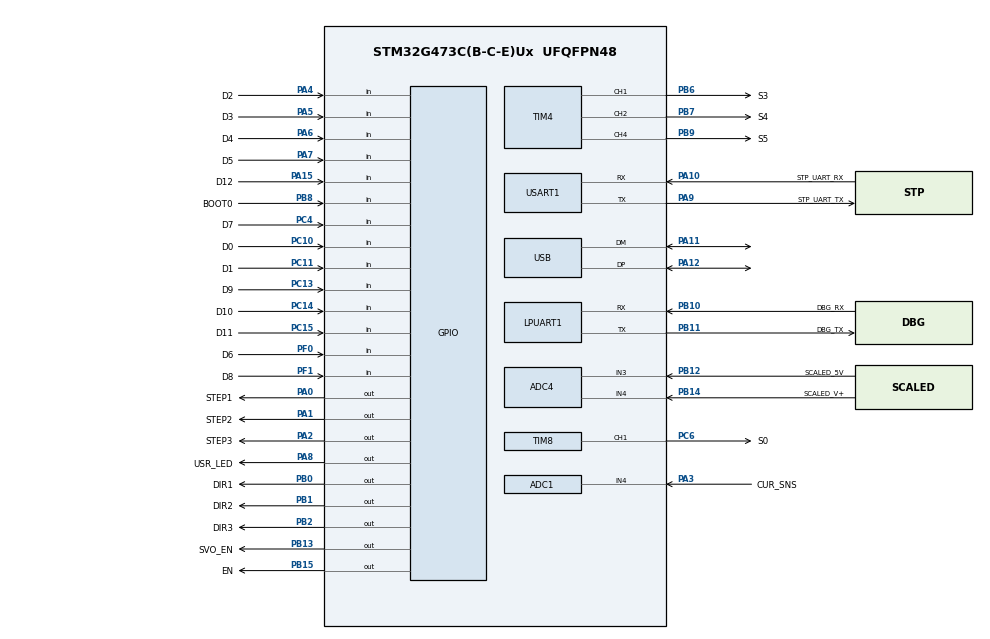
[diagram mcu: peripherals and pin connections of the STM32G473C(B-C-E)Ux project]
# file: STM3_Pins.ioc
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ADC1.Channel-0\#ChannelRegularConversion=ADC_CHANNEL_4
ADC1.NbrOfConversionFlag=1
ADC1.OffsetNumber-0\#ChannelRegularConversion=ADC_OFFSET_NONE
ADC1.Rank-0\#ChannelRegularConversion=1
ADC1.SamplingTime-0\#ChannelRegularConversion=ADC_SAMPLETIME_2CYCLES_5
ADC1.master=1
ADC4.Channel-0\#ChannelRegularConversion=ADC_CHANNEL_3
ADC4.NbrOfConversionFlag=1
ADC4.OffsetNumber-0\#ChannelRegularConversion=ADC_OFFSET_NONE
ADC4.Rank-0\#ChannelRegularConversion=1
ADC4.SamplingTime-0\#ChannelRegularConversion=ADC_SAMPLETIME_2CYCLES_5
Mcu.Family=STM32G4
Mcu.Name=STM32G473C(B-C-E)Ux
Mcu.Package=UFQFPN48
NVIC.PriorityGroup=NVIC_PRIORITYGROUP_4
NVIC.TIM6_DAC_IRQn=true\:0\:0\:false\:false\:true\:true\:true
NVIC.USB_LP_IRQn=true\:0\:0\:false\:false\:true\:false\:true
PA0.GPIO_Label=STEP1
PA0.Signal=GPIO_Output
PA1.GPIO_Label=STEP2
PA1.Signal=GPIO_Output
PA10.GPIO_Label=STP_UART_RX
PA10.Mode=Asynchronous
PA10.Signal=USART1_RX
PA11.Mode=Device
PA11.Signal=USB_DM
PA12.Mode=Device
PA12.Signal=USB_DP
PA13.GPIO_Label=SWDIO
PA13.Mode=Serial_Wire
PA13.Signal=SYS_JTMS-SWDIO
PA14.GPIO_Label=SWCLK
PA14.Mode=Serial_Wire
PA14.Signal=SYS_JTCK-SWCLK
PA15.GPIO_Label=D12
PA15.Signal=GPIO_Input
PA2.GPIO_Label=STEP3
PA2.Signal=GPIO_Output
PA3.GPIO_Label=CUR_SNS
PA3.Mode=IN4-Single-Ended
PA3.Signal=ADC1_IN4
PA4.GPIO_Label=D2
PA4.Signal=GPIO_Input
PA5.GPIO_Label=D3
PA5.Signal=GPIO_Input
PA6.GPIO_Label=D4
PA6.Signal=GPIO_Input
PA7.GPIO_Label=D5
PA7.Signal=GPIO_Input
PA8.GPIO_Label=USR_LED
PA8.Signal=GPIO_Output
PA9.GPIO_Label=STP_UART_TX
PA9.Mode=Asynchronous
PA9.Signal=USART1_TX
PB0.GPIO_Label=DIR1
PB0.Signal=GPIO_Output
PB1.GPIO_Label=DIR2
PB1.Signal=GPIO_Output
PB10.GPIO_Label=DBG_RX
PB10.Mode=Asynchronous
PB10.Signal=LPUART1_RX
PB11.GPIO_Label=DBG_TX
PB11.Mode=Asynchronous
PB11.Signal=LPUART1_TX
PB12.GPIO_Label=SCALED_5V
PB12.Mode=IN3-Single-Ended
PB12.Signal=ADC4_IN3
PB13.GPIO_Label=SVO_EN
PB13.Signal=GPIO_Output
PB14.GPIO_Label=SCALED_V+
PB14.Mode=IN4-Single-Ended
PB14.Signal=ADC4_IN4
PB15.GPIO_Label=EN
PB15.Signal=GPIO_Output
PB2.GPIO_Label=DIR3
PB2.Signal=GPIO_Output
PB3.GPIO_Label=SWO
PB3.Signal=SYS_JTDO-SWO
PB4.GPIO_Label=S1
PB4.Signal=S_TIM3_CH1
PB5.GPIO_Label=S2
PB5.Signal=S_TIM3_CH2
PB6.GPIO_Label=S3
PB6.Signal=S_TIM4_CH1
PB7.GPIO_Label=S4
PB7.Signal=S_TIM4_CH2
PB8-BOOT0.GPIO_Label=BOOT0
PB8-BOOT0.Signal=GPIO_Input
PB9.GPIO_Label=S5
PB9.Signal=S_TIM4_CH4
PC10.GPIO_Label=D0
PC10.Signal=GPIO_Input
PC11.GPIO_Label=D1
PC11.Signal=GPIO_Input
PC13.GPIO_Label=D9
PC13.Signal=GPIO_Input
PC14-OSC32_IN.GPIO_Label=D10
PC14-OSC32_IN.Signal=GPIO_Input
PC15-OSC32_OUT.GPIO_Label=D11
PC15-OSC32_OUT.Signal=GPIO_Input
PC4.GPIO_Label=D7
PC4.Signal=GPIO_Input
PC6.GPIO_Label=S0
PC6.Signal=S_TIM8_CH1
PF0-OSC_IN.GPIO_Label=D6
PF0-OSC_IN.Signal=GPIO_Input
PF1-OSC_OUT.GPIO_Label=D8
PF1-OSC_OUT.Signal=GPIO_Input
ProjectManager.HeapSize=0x200
ProjectManager.StackSize=0x400
ProjectManager.TargetToolchain=STM32CubeIDE
RCC.ADC12Freq_Value=150000000
RCC.ADC345Freq_Value=150000000
RCC.AHBFreq_Value=150000000
RCC.APB1Freq_Value=150000000
RCC.APB1TimFreq_Value=150000000
RCC.APB2Freq_Value=150000000
RCC.APB2TimFreq_Value=150000000
RCC.CK48CLockSelection=RCC_USBCLKSOURCE_HSI48
RCC.CortexFreq_Value=150000000
RCC.EXTERNAL_CLOCK_VALUE=12288000
RCC.HCLKFreq_Value=150000000
RCC.HSE_VALUE=8000000
RCC.HSI48_VALUE=48000000
RCC.HSI_VALUE=16000000
RCC.LSE_VALUE=32768
RCC.PLLM=RCC_PLLM_DIV4
RCC.PLLN=75
RCC.PLLQ=RCC_PLLQ_DIV6
RCC.SYSCLKFreq_VALUE=150000000
RCC.SYSCLKSource=RCC_SYSCLKSOURCE_PLLCLK
RCC.USBFreq_Value=48000000
RCC.VCOOutputFreq_Value=300000000
SH.S_TIM3_CH1.0=TIM3_CH1
SH.S_TIM3_CH2.0=TIM3_CH2
SH.S_TIM4_CH1.0=TIM4_CH1,Output Compare1 CH1
SH.S_TIM4_CH2.0=TIM4_CH2,Output Compare2 CH2
SH.S_TIM4_CH4.0=TIM4_CH4,Output Compare4 CH4
SH.S_TIM8_CH1.0=TIM8_CH1,PWM Generation1 CH1
TIM4.Channel-Output\ Compare1\ CH1=TIM_CHANNEL_1
TIM4.Channel-Output\ Compare2\ CH2=TIM_CHANNEL_2
TIM4.Channel-Output\ Compare4\ CH4=TIM_CHANNEL_4
TIM6.PeriodNoDither=1700
TIM8.Channel-PWM\ Generation1\ CH1=TIM_CHANNEL_1
USART1.VirtualMode-Asynchronous=VM_ASYNC
USB_DEVICE.CLASS_NAME_FS=CDC
USB_DEVICE.VirtualMode=Cdc
USB_DEVICE.VirtualModeFS=Cdc_FS
VP_RCC_VS_USB.Mode=USB_FS
VP_SYS_VS_DBSignals.Mode=DisableDeadBatterySignals
VP_TIM2_VS_ClockSourceINT.Mode=Internal
VP_TIM3_VS_ClockSourceINT.Mode=Internal
VP_TIM4_VS_ClockSourceINT.Mode=Internal
VP_TIM6_VS_ClockSourceINT.Mode=Enable_Timer
VP_TIM8_VS_ClockSourceINT.Mode=Internal
VP_USB_DEVICE_VS_USB_DEVICE_CDC_FS.Mode=CDC_FS
board=custom

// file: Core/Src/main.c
/* USER CODE BEGIN Header */
/**
  ******************************************************************************
  * @file           : main.c
  * @brief          : Main program body
  ******************************************************************************
  * @attention
  *
  * <h2><center>&copy; Copyright (c) 2020 STMicroelectronics.
  * All rights reserved.</center></h2>
  *
  * This software component is licensed by ST under BSD 3-Clause license,
  * the "License"; You may not use this file except in compliance with the
  * License. You may obtain a copy of the License at:
  *                        opensource.org/licenses/BSD-3-Clause
  *
  ******************************************************************************
  */
/* USER CODE END Header */
#include "main.h"
#include "usb_device.h"

/* USER CODE BEGIN Includes */
#include "usbd_cdc_if.h"
#include "retarget.h"
#include "isr.h"
#include "debug.h"

/* USER CODE END Includes */

ADC_HandleTypeDef hadc1;
ADC_HandleTypeDef hadc4;

UART_HandleTypeDef hlpuart1;
UART_HandleTypeDef huart1;

TIM_HandleTypeDef htim2;
TIM_HandleTypeDef htim3;
TIM_HandleTypeDef htim4;
TIM_HandleTypeDef htim6;
TIM_HandleTypeDef htim8;

void SystemClock_Config(void);
static void MX_GPIO_Init(void);
static void MX_TIM2_Init(void);
static void MX_TIM3_Init(void);
static void MX_TIM4_Init(void);
static void MX_USART1_UART_Init(void);
static void MX_ADC4_Init(void);
static void MX_LPUART1_UART_Init(void);
static void MX_ADC1_Init(void);
static void MX_TIM8_Init(void);
static void MX_TIM6_Init(void);

/* USER CODE BEGIN 0 */

void HAL_TIM_PeriodElapsedCallback(TIM_HandleTypeDef *htim)
{
  if (htim == &htim6)
  {
    high_ISR();
  }
}

/* USER CODE END 0 */

int main(void)
{

  /* MCU Configuration--------------------------------------------------------*/

  /* Reset of all peripherals, Initializes the Flash interface and the Systick. */
  HAL_Init();

  /* Configure the system clock */
  SystemClock_Config();

  /* Initialize all configured peripherals */
  MX_GPIO_Init();
  MX_USB_Device_Init();
  MX_TIM2_Init();
  MX_TIM3_Init();
  MX_TIM4_Init();
  MX_USART1_UART_Init();
  MX_ADC4_Init();
  MX_LPUART1_UART_Init();
  MX_ADC1_Init();
  MX_TIM8_Init();
  MX_TIM6_Init();
  /* USER CODE BEGIN 2 */
  RetargetInit();
  DebugInit();
  /* USER CODE END 2 */

  /* Infinite loop */
  /* USER CODE BEGIN WHILE */
  while (1)
  {
    DEBUG_G0_SET();
    DEBUG_G0_RESET();
    /* USER CODE END WHILE */

  }
}

void SystemClock_Config(void)
{
  RCC_OscInitTypeDef RCC_OscInitStruct = {0};
  RCC_ClkInitTypeDef RCC_ClkInitStruct = {0};
  RCC_PeriphCLKInitTypeDef PeriphClkInit = {0};
  RCC_CRSInitTypeDef pInit = {0};

  /** Configure the main internal regulator output voltage
  */
  HAL_PWREx_ControlVoltageScaling(PWR_REGULATOR_VOLTAGE_SCALE1_BOOST);
  /** Initializes the RCC Oscillators according to the specified parameters
  * in the RCC_OscInitTypeDef structure.
  */
  RCC_OscInitStruct.OscillatorType = RCC_OSCILLATORTYPE_HSI|RCC_OSCILLATORTYPE_HSI48;
  RCC_OscInitStruct.HSIState = RCC_HSI_ON;
  RCC_OscInitStruct.HSICalibrationValue = RCC_HSICALIBRATION_DEFAULT;
  RCC_OscInitStruct.HSI48State = RCC_HSI48_ON;
  RCC_OscInitStruct.PLL.PLLState = RCC_PLL_ON;
  RCC_OscInitStruct.PLL.PLLSource = RCC_PLLSOURCE_HSI;
  RCC_OscInitStruct.PLL.PLLM = RCC_PLLM_DIV4;
  RCC_OscInitStruct.PLL.PLLN = 85;
  RCC_OscInitStruct.PLL.PLLP = RCC_PLLP_DIV2;
  RCC_OscInitStruct.PLL.PLLQ = RCC_PLLQ_DIV6;
  RCC_OscInitStruct.PLL.PLLR = RCC_PLLR_DIV2;
  if (HAL_RCC_OscConfig(&RCC_OscInitStruct) != HAL_OK)
  {
    Error_Handler();
  }
  /** Initializes the CPU, AHB and APB buses clocks
  */
  RCC_ClkInitStruct.ClockType = RCC_CLOCKTYPE_HCLK|RCC_CLOCKTYPE_SYSCLK
                              |RCC_CLOCKTYPE_PCLK1|RCC_CLOCKTYPE_PCLK2;
  RCC_ClkInitStruct.SYSCLKSource = RCC_SYSCLKSOURCE_PLLCLK;
  RCC_ClkInitStruct.AHBCLKDivider = RCC_SYSCLK_DIV1;
  RCC_ClkInitStruct.APB1CLKDivider = RCC_HCLK_DIV1;
  RCC_ClkInitStruct.APB2CLKDivider = RCC_HCLK_DIV1;

  if (HAL_RCC_ClockConfig(&RCC_ClkInitStruct, FLASH_LATENCY_4) != HAL_OK)
  {
    Error_Handler();
  }
  /** Initializes the peripherals clocks
  */
  PeriphClkInit.PeriphClockSelection = RCC_PERIPHCLK_USART1|RCC_PERIPHCLK_LPUART1
                              |RCC_PERIPHCLK_USB|RCC_PERIPHCLK_ADC12
                              |RCC_PERIPHCLK_ADC345;
  PeriphClkInit.Usart1ClockSelection = RCC_USART1CLKSOURCE_PCLK2;
  PeriphClkInit.Lpuart1ClockSelection = RCC_LPUART1CLKSOURCE_PCLK1;
  PeriphClkInit.UsbClockSelection = RCC_USBCLKSOURCE_HSI48;
  PeriphClkInit.Adc12ClockSelection = RCC_ADC12CLKSOURCE_SYSCLK;
  PeriphClkInit.Adc345ClockSelection = RCC_ADC345CLKSOURCE_SYSCLK;
  if (HAL_RCCEx_PeriphCLKConfig(&PeriphClkInit) != HAL_OK)
  {
    Error_Handler();
  }
  /** Configures CRS
  */
  pInit.Prescaler = RCC_CRS_SYNC_DIV1;
  pInit.Source = RCC_CRS_SYNC_SOURCE_USB;
  pInit.Polarity = RCC_CRS_SYNC_POLARITY_RISING;
  pInit.ReloadValue = __HAL_RCC_CRS_RELOADVALUE_CALCULATE(48000000,1000);
  pInit.ErrorLimitValue = 34;
  pInit.HSI48CalibrationValue = 32;

  HAL_RCCEx_CRSConfig(&pInit);
}

static void MX_ADC1_Init(void)
{

  ADC_MultiModeTypeDef multimode = {0};
  ADC_ChannelConfTypeDef sConfig = {0};

  /** Common config
  */
  hadc1.Instance = ADC1;
  hadc1.Init.ClockPrescaler = ADC_CLOCK_SYNC_PCLK_DIV4;
  hadc1.Init.Resolution = ADC_RESOLUTION_12B;
  hadc1.Init.DataAlign = ADC_DATAALIGN_RIGHT;
  hadc1.Init.GainCompensation = 0;
  hadc1.Init.ScanConvMode = ADC_SCAN_DISABLE;
  hadc1.Init.EOCSelection = ADC_EOC_SINGLE_CONV;
  hadc1.Init.LowPowerAutoWait = DISABLE;
  hadc1.Init.ContinuousConvMode = DISABLE;
  hadc1.Init.NbrOfConversion = 1;
  hadc1.Init.DiscontinuousConvMode = DISABLE;
  hadc1.Init.ExternalTrigConv = ADC_SOFTWARE_START;
  hadc1.Init.ExternalTrigConvEdge = ADC_EXTERNALTRIGCONVEDGE_NONE;
  hadc1.Init.DMAContinuousRequests = DISABLE;
  hadc1.Init.Overrun = ADC_OVR_DATA_PRESERVED;
  hadc1.Init.OversamplingMode = DISABLE;
  if (HAL_ADC_Init(&hadc1) != HAL_OK)
  {
    Error_Handler();
  }
  /** Configure the ADC multi-mode
  */
  multimode.Mode = ADC_MODE_INDEPENDENT;
  if (HAL_ADCEx_MultiModeConfigChannel(&hadc1, &multimode) != HAL_OK)
  {
    Error_Handler();
  }
  /** Configure Regular Channel
  */
  sConfig.Channel = ADC_CHANNEL_4;
  sConfig.Rank = ADC_REGULAR_RANK_1;
  sConfig.SamplingTime = ADC_SAMPLETIME_2CYCLES_5;
  sConfig.SingleDiff = ADC_SINGLE_ENDED;
  sConfig.OffsetNumber = ADC_OFFSET_NONE;
  sConfig.Offset = 0;
  if (HAL_ADC_ConfigChannel(&hadc1, &sConfig) != HAL_OK)
  {
    Error_Handler();
  }

}

static void MX_ADC4_Init(void)
{

  ADC_ChannelConfTypeDef sConfig = {0};

  /** Common config
  */
  hadc4.Instance = ADC4;
  hadc4.Init.ClockPrescaler = ADC_CLOCK_SYNC_PCLK_DIV4;
  hadc4.Init.Resolution = ADC_RESOLUTION_12B;
  hadc4.Init.DataAlign = ADC_DATAALIGN_RIGHT;
  hadc4.Init.GainCompensation = 0;
  hadc4.Init.ScanConvMode = ADC_SCAN_DISABLE;
  hadc4.Init.EOCSelection = ADC_EOC_SINGLE_CONV;
  hadc4.Init.LowPowerAutoWait = DISABLE;
  hadc4.Init.ContinuousConvMode = DISABLE;
  hadc4.Init.NbrOfConversion = 1;
  hadc4.Init.DiscontinuousConvMode = DISABLE;
  hadc4.Init.ExternalTrigConv = ADC_SOFTWARE_START;
  hadc4.Init.ExternalTrigConvEdge = ADC_EXTERNALTRIGCONVEDGE_NONE;
  hadc4.Init.DMAContinuousRequests = DISABLE;
  hadc4.Init.Overrun = ADC_OVR_DATA_PRESERVED;
  hadc4.Init.OversamplingMode = DISABLE;
  if (HAL_ADC_Init(&hadc4) != HAL_OK)
  {
    Error_Handler();
  }
  /** Configure Regular Channel
  */
  sConfig.Channel = ADC_CHANNEL_3;
  sConfig.Rank = ADC_REGULAR_RANK_1;
  sConfig.SamplingTime = ADC_SAMPLETIME_2CYCLES_5;
  sConfig.SingleDiff = ADC_SINGLE_ENDED;
  sConfig.OffsetNumber = ADC_OFFSET_NONE;
  sConfig.Offset = 0;
  if (HAL_ADC_ConfigChannel(&hadc4, &sConfig) != HAL_OK)
  {
    Error_Handler();
  }

}

static void MX_LPUART1_UART_Init(void)
{

  hlpuart1.Instance = LPUART1;
  hlpuart1.Init.BaudRate = 209700;
  hlpuart1.Init.WordLength = UART_WORDLENGTH_8B;
  hlpuart1.Init.StopBits = UART_STOPBITS_1;
  hlpuart1.Init.Parity = UART_PARITY_NONE;
  hlpuart1.Init.Mode = UART_MODE_TX_RX;
  hlpuart1.Init.HwFlowCtl = UART_HWCONTROL_NONE;
  hlpuart1.Init.OneBitSampling = UART_ONE_BIT_SAMPLE_DISABLE;
  hlpuart1.AdvancedInit.AdvFeatureInit = UART_ADVFEATURE_NO_INIT;
  if (HAL_UART_Init(&hlpuart1) != HAL_OK)
  {
    Error_Handler();
  }
  if (HAL_UARTEx_SetTxFifoThreshold(&hlpuart1, UART_TXFIFO_THRESHOLD_1_8) != HAL_OK)
  {
    Error_Handler();
  }
  if (HAL_UARTEx_SetRxFifoThreshold(&hlpuart1, UART_RXFIFO_THRESHOLD_1_8) != HAL_OK)
  {
    Error_Handler();
  }
  if (HAL_UARTEx_DisableFifoMode(&hlpuart1) != HAL_OK)
  {
    Error_Handler();
  }

}

static void MX_USART1_UART_Init(void)
{

  huart1.Instance = USART1;
  huart1.Init.BaudRate = 115200;
  huart1.Init.WordLength = UART_WORDLENGTH_8B;
  huart1.Init.StopBits = UART_STOPBITS_1;
  huart1.Init.Parity = UART_PARITY_NONE;
  huart1.Init.Mode = UART_MODE_TX_RX;
  huart1.Init.HwFlowCtl = UART_HWCONTROL_NONE;
  huart1.Init.OverSampling = UART_OVERSAMPLING_16;
  huart1.Init.OneBitSampling = UART_ONE_BIT_SAMPLE_DISABLE;
  huart1.Init.ClockPrescaler = UART_PRESCALER_DIV1;
  huart1.AdvancedInit.AdvFeatureInit = UART_ADVFEATURE_NO_INIT;
  if (HAL_UART_Init(&huart1) != HAL_OK)
  {
    Error_Handler();
  }
  if (HAL_UARTEx_SetTxFifoThreshold(&huart1, UART_TXFIFO_THRESHOLD_1_8) != HAL_OK)
  {
    Error_Handler();
  }
  if (HAL_UARTEx_SetRxFifoThreshold(&huart1, UART_RXFIFO_THRESHOLD_1_8) != HAL_OK)
  {
    Error_Handler();
  }
  if (HAL_UARTEx_DisableFifoMode(&huart1) != HAL_OK)
  {
    Error_Handler();
  }

}

static void MX_TIM2_Init(void)
{

  TIM_ClockConfigTypeDef sClockSourceConfig = {0};
  TIM_MasterConfigTypeDef sMasterConfig = {0};

  htim2.Instance = TIM2;
  htim2.Init.Prescaler = 0;
  htim2.Init.CounterMode = TIM_COUNTERMODE_UP;
  htim2.Init.Period = 4.294967295E9;
  htim2.Init.ClockDivision = TIM_CLOCKDIVISION_DIV1;
  htim2.Init.AutoReloadPreload = TIM_AUTORELOAD_PRELOAD_DISABLE;
  if (HAL_TIM_Base_Init(&htim2) != HAL_OK)
  {
    Error_Handler();
  }
  sClockSourceConfig.ClockSource = TIM_CLOCKSOURCE_INTERNAL;
  if (HAL_TIM_ConfigClockSource(&htim2, &sClockSourceConfig) != HAL_OK)
  {
    Error_Handler();
  }
  sMasterConfig.MasterOutputTrigger = TIM_TRGO_RESET;
  sMasterConfig.MasterSlaveMode = TIM_MASTERSLAVEMODE_DISABLE;
  if (HAL_TIMEx_MasterConfigSynchronization(&htim2, &sMasterConfig) != HAL_OK)
  {
    Error_Handler();
  }

}

static void MX_TIM3_Init(void)
{

  TIM_ClockConfigTypeDef sClockSourceConfig = {0};
  TIM_MasterConfigTypeDef sMasterConfig = {0};

  htim3.Instance = TIM3;
  htim3.Init.Prescaler = 0;
  htim3.Init.CounterMode = TIM_COUNTERMODE_UP;
  htim3.Init.Period = 65535;
  htim3.Init.ClockDivision = TIM_CLOCKDIVISION_DIV1;
  htim3.Init.AutoReloadPreload = TIM_AUTORELOAD_PRELOAD_DISABLE;
  if (HAL_TIM_Base_Init(&htim3) != HAL_OK)
  {
    Error_Handler();
  }
  sClockSourceConfig.ClockSource = TIM_CLOCKSOURCE_INTERNAL;
  if (HAL_TIM_ConfigClockSource(&htim3, &sClockSourceConfig) != HAL_OK)
  {
    Error_Handler();
  }
  sMasterConfig.MasterOutputTrigger = TIM_TRGO_RESET;
  sMasterConfig.MasterSlaveMode = TIM_MASTERSLAVEMODE_DISABLE;
  if (HAL_TIMEx_MasterConfigSynchronization(&htim3, &sMasterConfig) != HAL_OK)
  {
    Error_Handler();
  }

}

static void MX_TIM4_Init(void)
{

  TIM_ClockConfigTypeDef sClockSourceConfig = {0};
  TIM_MasterConfigTypeDef sMasterConfig = {0};
  TIM_OC_InitTypeDef sConfigOC = {0};

  htim4.Instance = TIM4;
  htim4.Init.Prescaler = 0;
  htim4.Init.CounterMode = TIM_COUNTERMODE_UP;
  htim4.Init.Period = 65535;
  htim4.Init.ClockDivision = TIM_CLOCKDIVISION_DIV1;
  htim4.Init.AutoReloadPreload = TIM_AUTORELOAD_PRELOAD_DISABLE;
  if (HAL_TIM_Base_Init(&htim4) != HAL_OK)
  {
    Error_Handler();
  }
  sClockSourceConfig.ClockSource = TIM_CLOCKSOURCE_INTERNAL;
  if (HAL_TIM_ConfigClockSource(&htim4, &sClockSourceConfig) != HAL_OK)
  {
    Error_Handler();
  }
  if (HAL_TIM_OC_Init(&htim4) != HAL_OK)
  {
    Error_Handler();
  }
  sMasterConfig.MasterOutputTrigger = TIM_TRGO_RESET;
  sMasterConfig.MasterSlaveMode = TIM_MASTERSLAVEMODE_DISABLE;
  if (HAL_TIMEx_MasterConfigSynchronization(&htim4, &sMasterConfig) != HAL_OK)
  {
    Error_Handler();
  }
  sConfigOC.OCMode = TIM_OCMODE_TIMING;
  sConfigOC.Pulse = 0;
  sConfigOC.OCPolarity = TIM_OCPOLARITY_HIGH;
  sConfigOC.OCFastMode = TIM_OCFAST_DISABLE;
  if (HAL_TIM_OC_ConfigChannel(&htim4, &sConfigOC, TIM_CHANNEL_1) != HAL_OK)
  {
    Error_Handler();
  }
  sConfigOC.Pulse = 0;
  if (HAL_TIM_OC_ConfigChannel(&htim4, &sConfigOC, TIM_CHANNEL_2) != HAL_OK)
  {
    Error_Handler();
  }
  sConfigOC.Pulse = 0;
  if (HAL_TIM_OC_ConfigChannel(&htim4, &sConfigOC, TIM_CHANNEL_4) != HAL_OK)
  {
    Error_Handler();
  }
  HAL_TIM_MspPostInit(&htim4);

}

static void MX_TIM6_Init(void)
{

  TIM_MasterConfigTypeDef sMasterConfig = {0};

  htim6.Instance = TIM6;
  htim6.Init.Prescaler = 0;
  htim6.Init.CounterMode = TIM_COUNTERMODE_UP;
  htim6.Init.Period = 1700;
  htim6.Init.AutoReloadPreload = TIM_AUTORELOAD_PRELOAD_DISABLE;
  if (HAL_TIM_Base_Init(&htim6) != HAL_OK)
  {
    Error_Handler();
  }
  sMasterConfig.MasterOutputTrigger = TIM_TRGO_RESET;
  sMasterConfig.MasterSlaveMode = TIM_MASTERSLAVEMODE_DISABLE;
  if (HAL_TIMEx_MasterConfigSynchronization(&htim6, &sMasterConfig) != HAL_OK)
  {
    Error_Handler();
  }
  /* USER CODE BEGIN TIM6_Init 2 */

  if (HAL_TIM_Base_Start_IT(&htim6) != HAL_OK)
  {
    Error_Handler();
  }

  /* USER CODE END TIM6_Init 2 */

}

static void MX_TIM8_Init(void)
{

  TIM_ClockConfigTypeDef sClockSourceConfig = {0};
  TIM_MasterConfigTypeDef sMasterConfig = {0};
  TIM_OC_InitTypeDef sConfigOC = {0};
  TIM_BreakDeadTimeConfigTypeDef sBreakDeadTimeConfig = {0};

  htim8.Instance = TIM8;
  htim8.Init.Prescaler = 0;
  htim8.Init.CounterMode = TIM_COUNTERMODE_UP;
  htim8.Init.Period = 65535;
  htim8.Init.ClockDivision = TIM_CLOCKDIVISION_DIV1;
  htim8.Init.RepetitionCounter = 0;
  htim8.Init.AutoReloadPreload = TIM_AUTORELOAD_PRELOAD_DISABLE;
  if (HAL_TIM_Base_Init(&htim8) != HAL_OK)
  {
    Error_Handler();
  }
  sClockSourceConfig.ClockSource = TIM_CLOCKSOURCE_INTERNAL;
  if (HAL_TIM_ConfigClockSource(&htim8, &sClockSourceConfig) != HAL_OK)
  {
    Error_Handler();
  }
  if (HAL_TIM_PWM_Init(&htim8) != HAL_OK)
  {
    Error_Handler();
  }
  sMasterConfig.MasterOutputTrigger = TIM_TRGO_RESET;
  sMasterConfig.MasterOutputTrigger2 = TIM_TRGO2_RESET;
  sMasterConfig.MasterSlaveMode = TIM_MASTERSLAVEMODE_DISABLE;
  if (HAL_TIMEx_MasterConfigSynchronization(&htim8, &sMasterConfig) != HAL_OK)
  {
    Error_Handler();
  }
  sConfigOC.OCMode = TIM_OCMODE_PWM1;
  sConfigOC.Pulse = 0;
  sConfigOC.OCPolarity = TIM_OCPOLARITY_HIGH;
  sConfigOC.OCNPolarity = TIM_OCNPOLARITY_HIGH;
  sConfigOC.OCFastMode = TIM_OCFAST_DISABLE;
  sConfigOC.OCIdleState = TIM_OCIDLESTATE_RESET;
  sConfigOC.OCNIdleState = TIM_OCNIDLESTATE_RESET;
  if (HAL_TIM_PWM_ConfigChannel(&htim8, &sConfigOC, TIM_CHANNEL_1) != HAL_OK)
  {
    Error_Handler();
  }
  sBreakDeadTimeConfig.OffStateRunMode = TIM_OSSR_DISABLE;
  sBreakDeadTimeConfig.OffStateIDLEMode = TIM_OSSI_DISABLE;
  sBreakDeadTimeConfig.LockLevel = TIM_LOCKLEVEL_OFF;
  sBreakDeadTimeConfig.DeadTime = 0;
  sBreakDeadTimeConfig.BreakState = TIM_BREAK_DISABLE;
  sBreakDeadTimeConfig.BreakPolarity = TIM_BREAKPOLARITY_HIGH;
  sBreakDeadTimeConfig.BreakFilter = 0;
  sBreakDeadTimeConfig.BreakAFMode = TIM_BREAK_AFMODE_INPUT;
  sBreakDeadTimeConfig.Break2State = TIM_BREAK2_DISABLE;
  sBreakDeadTimeConfig.Break2Polarity = TIM_BREAK2POLARITY_HIGH;
  sBreakDeadTimeConfig.Break2Filter = 0;
  sBreakDeadTimeConfig.Break2AFMode = TIM_BREAK_AFMODE_INPUT;
  sBreakDeadTimeConfig.AutomaticOutput = TIM_AUTOMATICOUTPUT_DISABLE;
  if (HAL_TIMEx_ConfigBreakDeadTime(&htim8, &sBreakDeadTimeConfig) != HAL_OK)
  {
    Error_Handler();
  }
  HAL_TIM_MspPostInit(&htim8);

}

static void MX_GPIO_Init(void)
{
  GPIO_InitTypeDef GPIO_InitStruct = {0};

  /* GPIO Ports Clock Enable */
  __HAL_RCC_GPIOC_CLK_ENABLE();
  __HAL_RCC_GPIOF_CLK_ENABLE();
  __HAL_RCC_GPIOG_CLK_ENABLE();
  __HAL_RCC_GPIOA_CLK_ENABLE();
  __HAL_RCC_GPIOB_CLK_ENABLE();

  /*Configure GPIO pin Output Level */
  HAL_GPIO_WritePin(GPIOA, STEP1_Pin|STEP2_Pin|STEP3_Pin|USR_LED_Pin, GPIO_PIN_RESET);

  /*Configure GPIO pin Output Level */
  HAL_GPIO_WritePin(GPIOB, DIR1_Pin|DIR2_Pin|DIR3_Pin|SVO_EN_Pin
                          |EN_Pin, GPIO_PIN_RESET);

  /*Configure GPIO pins : G9_Pin G10_Pin G11_Pin G7_Pin
                           G0_Pin G1_Pin */
  GPIO_InitStruct.Pin = G9_Pin|G10_Pin|G11_Pin|G7_Pin
                          |G0_Pin|G1_Pin;
  GPIO_InitStruct.Mode = GPIO_MODE_INPUT;
  GPIO_InitStruct.Pull = GPIO_NOPULL;
  HAL_GPIO_Init(GPIOC, &GPIO_InitStruct);

  /*Configure GPIO pins : G6_Pin G8_Pin */
  GPIO_InitStruct.Pin = G6_Pin|G8_Pin;
  GPIO_InitStruct.Mode = GPIO_MODE_INPUT;
  GPIO_InitStruct.Pull = GPIO_NOPULL;
  HAL_GPIO_Init(GPIOF, &GPIO_InitStruct);

  /*Configure GPIO pin : PG10 */
  GPIO_InitStruct.Pin = GPIO_PIN_10;
  GPIO_InitStruct.Mode = GPIO_MODE_AF_PP;
  GPIO_InitStruct.Pull = GPIO_NOPULL;
  GPIO_InitStruct.Speed = GPIO_SPEED_FREQ_LOW;
  GPIO_InitStruct.Alternate = GPIO_AF0_MCO;
  HAL_GPIO_Init(GPIOG, &GPIO_InitStruct);

  /*Configure GPIO pins : STEP1_Pin STEP2_Pin STEP3_Pin USR_LED_Pin */
  GPIO_InitStruct.Pin = STEP1_Pin|STEP2_Pin|STEP3_Pin|USR_LED_Pin;
  GPIO_InitStruct.Mode = GPIO_MODE_OUTPUT_PP;
  GPIO_InitStruct.Pull = GPIO_NOPULL;
  GPIO_InitStruct.Speed = GPIO_SPEED_FREQ_LOW;
  HAL_GPIO_Init(GPIOA, &GPIO_InitStruct);

  /*Configure GPIO pins : G2_Pin G3_Pin G4_Pin G5_Pin
                           G12_Pin */
  GPIO_InitStruct.Pin = G2_Pin|G3_Pin|G4_Pin|G5_Pin
                          |G12_Pin;
  GPIO_InitStruct.Mode = GPIO_MODE_INPUT;
  GPIO_InitStruct.Pull = GPIO_NOPULL;
  HAL_GPIO_Init(GPIOA, &GPIO_InitStruct);

  /*Configure GPIO pins : DIR1_Pin DIR2_Pin DIR3_Pin SVO_EN_Pin
                           EN_Pin */
  GPIO_InitStruct.Pin = DIR1_Pin|DIR2_Pin|DIR3_Pin|SVO_EN_Pin
                          |EN_Pin;
  GPIO_InitStruct.Mode = GPIO_MODE_OUTPUT_PP;
  GPIO_InitStruct.Pull = GPIO_NOPULL;
  GPIO_InitStruct.Speed = GPIO_SPEED_FREQ_LOW;
  HAL_GPIO_Init(GPIOB, &GPIO_InitStruct);

  /*Configure GPIO pin : BOOT0_Pin */
  GPIO_InitStruct.Pin = BOOT0_Pin;
  GPIO_InitStruct.Mode = GPIO_MODE_INPUT;
  GPIO_InitStruct.Pull = GPIO_NOPULL;
  HAL_GPIO_Init(BOOT0_GPIO_Port, &GPIO_InitStruct);

}

void Error_Handler(void)
{
}

/************************ (C) COPYRIGHT STMicroelectronics *****END OF FILE****/
